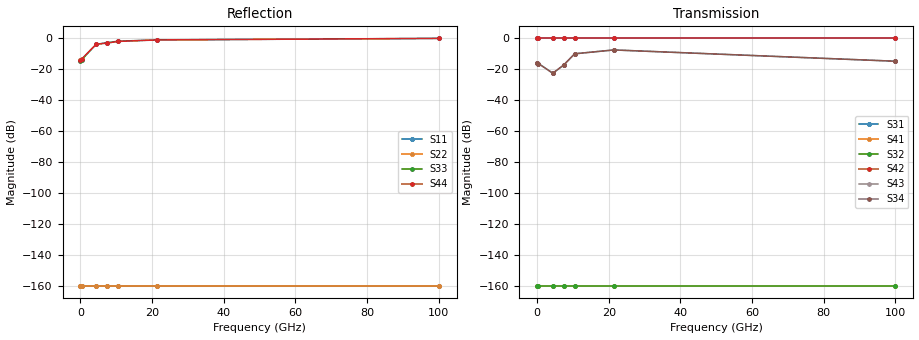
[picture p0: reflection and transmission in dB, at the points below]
! Touchstone Ver. 1.0
! Tue Jan 21 11:50:01 2014
! Number of ports is 4
# Hz	S	RI	R	50.000000
! SCATTERING PARAMETERS  :
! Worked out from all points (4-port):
!   1101 points, 1 Hz to 100 GHz, reference 50 ohm
!   strongest paths, dB at 1 Hz, 562.3 Hz, 316.2 kHz, 177.8 MHz, 100 GHz:
!     S42: 0.0, 0.0, 0.0, 0.0, 0.0
!     S31: 0.0, 0.0, 0.0, 0.0, 0.0
!     S43: -16.1, -16.1, -16.1, -16.2, -14.8
!     S41: -, -, -, -, -
!     S32: -, -, -, -, -
!     S21: -, -, -, -, -
!   lowest |S11| = - dB at 1 Hz (marker M1), VSWR 1.00, Z = 50 + j3.06e-25 ohm
!   |S11| at or under -10 dB: start of sweep to end of sweep
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1  -2.5e-11 3.06e-27  0 0  0 0  0 0
   0 0  -2.5e-11 3.06e-27  0 0  0 0
   1 9.57e-21  -3.9e-12 2.53e-21  0.1859 -3.83e-10  0.156 -1.01e-10
   -3.9e-12 2.54e-21  1 9.83e-21  0.156 -1.01e-10  0.1987 -3.93e-10
3.548134e8  -2.5e-11 3.06e-27  0 0  0 0  0 0
            0 0  -2.5e-11 3.06e-27  0 0  0 0
            1 2.77e-12  -3.77e-12 7.45e-13  0.1651 -0.1109  0.1509 -0.0298
            -3.77e-12 7.45e-13  1 2.91e-12  0.1509 -0.0298  0.1771 -0.1163
4.365158e9  -2.5e-11 3.06e-27  0 0  0 0  0 0
            0 0  -2.5e-11 3.06e-27  0 0  0 0
            1 -2.35e-12  1.46e-12 1.15e-12  -0.6203 0.0939  -0.0585 -0.0461
            1.46e-12 1.15e-12  1 -2.09e-12  -0.0585 -0.0461  -0.6237 0.0836
7.413102e9  -2.5e-11 3.06e-27  0 0  0 0  0 0
            0 0  -2.5e-11 3.06e-27  0 0  0 0
            1 -1.76e-11  2.6e-12 -2.24e-12  0.0687 0.7023  -0.104 0.0897
            2.6e-12 -2.24e-12  1 -1.71e-11  -0.104 0.0897  0.0749 0.6827
1.047129e10  -2.5e-11 3.06e-27  0 0  0 0  0 0
             0 0  -2.5e-11 3.06e-27  0 0  0 0
             1 2.21e-12  -2.26e-12 -7.59e-12  0.7856 -0.0883  0.0905 0.3037
             -2.26e-12 -7.59e-12  1 4.16e-12  0.0906 0.3037  0.7601 -0.1663
2.137962e10  -2.5e-11 3.06e-27  0 0  0 0  0 0
             0 0  -2.5e-11 3.06e-27  0 0  0 0
             1 1.64e-11  -6.99e-12 7.91e-12  -0.5765 -0.6578  0.2797 -0.3165
             -6.99e-12 7.91e-12  1 1.4e-11  0.2797 -0.3165  -0.6637 -0.5604
1e11  -2.5e-11 3.06e-27  0 0  0 0  0 0
      0 0  -2.5e-11 3.06e-27  0 0  0 0
      1 1.41e-12  2.12e-13 -4.55e-12  -0.973 -0.0565  -0.00847 0.1819
      2.12e-13 -4.55e-12  1 2.84e-12  -0.00847 0.1819  -0.9703 -0.1136
